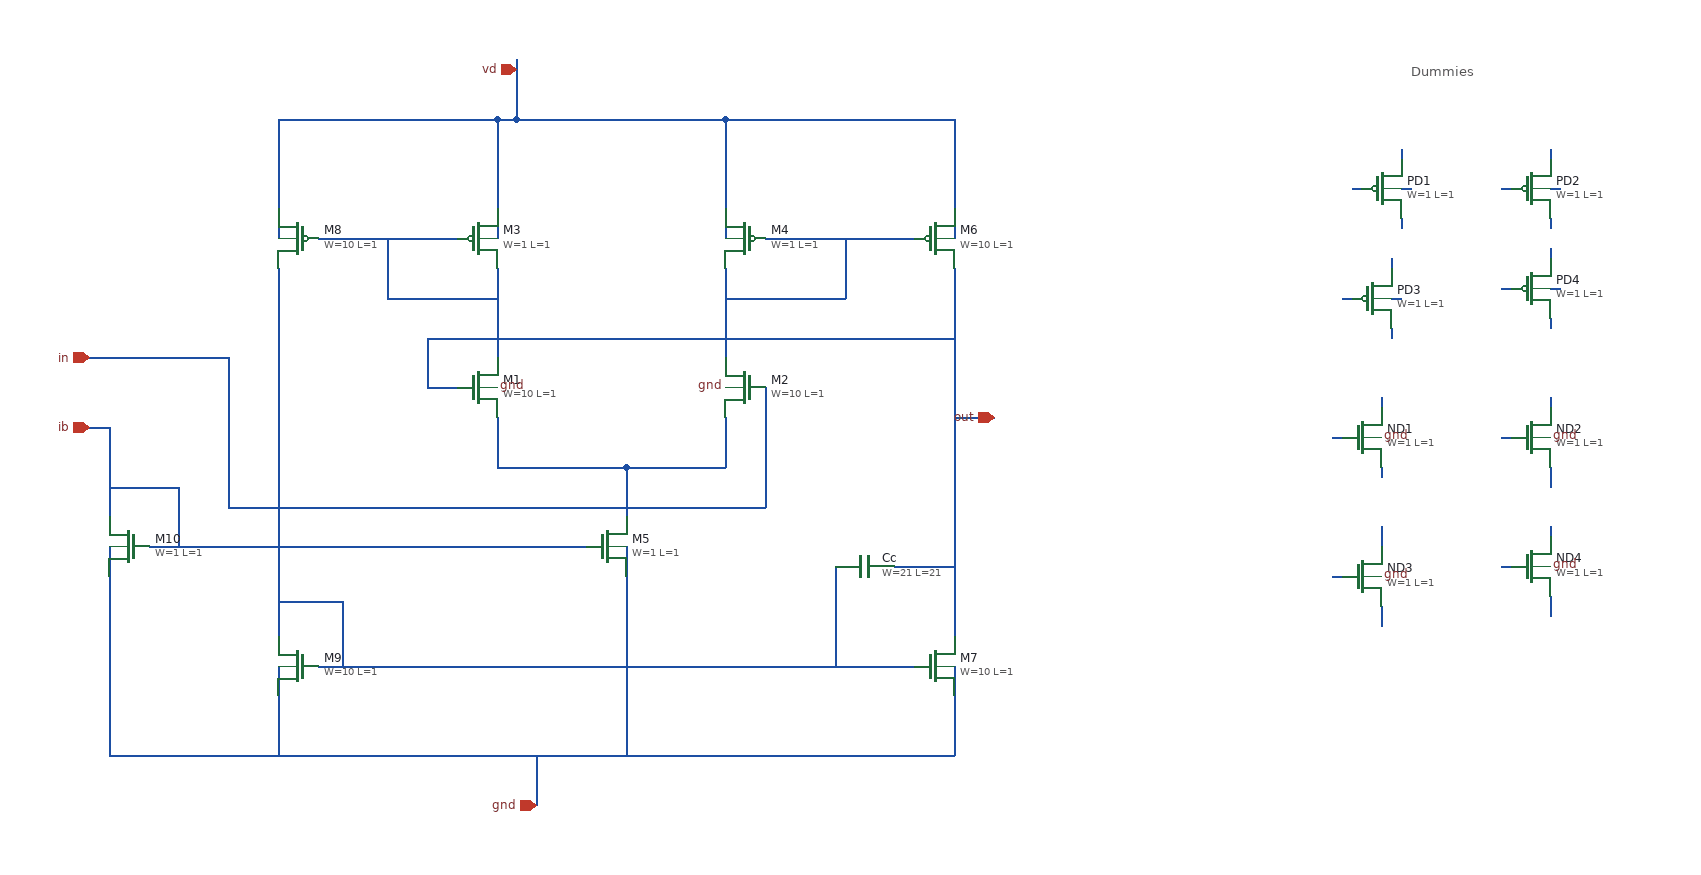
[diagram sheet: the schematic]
v {xschem version=3.4.2 file_version=1.2
* Copyright 2020 Stefan Frederik Schippers
* 
* Licensed under the Apache License, Version 2.0 (the "License");
* you may not use this file except in compliance with the License.
* You may obtain a copy of the License at
*
*     https://www.apache.org/licenses/LICENSE-2.0
*
* Unless required by applicable law or agreed to in writing, software
* distributed under the License is distributed on an "AS IS" BASIS,
* WITHOUT WARRANTIES OR CONDITIONS OF ANY KIND, either express or implied.
* See the License for the specific language governing permissions and
* limitations under the License.

}
G {}
K {}
V {}
S {}
E {}
T {Dummies} 1300 -1980 0 0 0.4 0.4 {}
N -40 -1610 -10 -1610 { lab=ib}
N 400 -1980 400 -1920 { lab=vd}
N 380 -1920 400 -1920 {
lab=vd}
N 380 -1920 380 -1830 {
lab=vd}
N 380 -1830 380 -1800 {
lab=vd}
N 160 -1920 380 -1920 {
lab=vd}
N 160 -1920 160 -1830 {
lab=vd}
N 400 -1920 610 -1920 {
lab=vd}
N 610 -1920 610 -1830 {
lab=vd}
N -10 -1610 -10 -1520 {
lab=ib}
N -10 -1490 -10 -1460 {
lab=gnd}
N 160 -1830 160 -1800 {
lab=vd}
N 610 -1830 610 -1800 {
lab=vd}
N 160 -1770 160 -1400 {
lab=#net1}
N 160 -1370 160 -1340 {
lab=gnd}
N 200 -1370 800 -1370 {
lab=#net1}
N 380 -1770 380 -1680 {
lab=#net2}
N 610 -1770 610 -1680 {
lab=#net3}
N 200 -1800 340 -1800 {
lab=#net2}
N 270 -1740 380 -1740 {
lab=#net2}
N 270 -1800 270 -1740 {
lab=#net2}
N 650 -1800 800 -1800 {
lab=#net3}
N 610 -1740 730 -1740 {
lab=#net3}
N 730 -1800 730 -1740 {
lab=#net3}
N 610 -1920 840 -1920 {
lab=vd}
N 840 -1920 840 -1830 {
lab=vd}
N 840 -1830 840 -1800 {
lab=vd}
N 840 -1770 840 -1400 {
lab=out}
N 840 -1370 840 -1340 {
lab=gnd}
N 840 -1620 880 -1620 {
lab=out}
N 310 -1650 340 -1650 {
lab=out}
N 310 -1700 310 -1650 {
lab=out}
N 310 -1700 840 -1700 {
lab=out}
N 30 -1490 470 -1490 {
lab=ib}
N 380 -1620 380 -1570 {
lab=#net4}
N 380 -1570 510 -1570 {
lab=#net4}
N 510 -1570 510 -1520 {
lab=#net4}
N 510 -1490 510 -1460 {
lab=gnd}
N 510 -1570 610 -1570 {
lab=#net4}
N 610 -1620 610 -1570 {
lab=#net4}
N 650 -1650 650 -1530 {
lab=in}
N 110 -1530 650 -1530 {
lab=in}
N 110 -1680 110 -1530 {
lab=in}
N -40 -1680 110 -1680 {
lab=in}
N -10 -1460 -10 -1280 {
lab=gnd}
N -10 -1280 840 -1280 {
lab=gnd}
N 840 -1340 840 -1280 {
lab=gnd}
N 160 -1340 160 -1280 {
lab=gnd}
N 510 -1460 510 -1280 {
lab=gnd}
N 420 -1280 420 -1230 {
lab=gnd}
N -10 -1550 60 -1550 {
lab=ib}
N 60 -1550 60 -1490 {
lab=ib}
N 160 -1435 225 -1435 {
lab=#net1}
N 225 -1435 225 -1370 {
lab=#net1}
N 1290 -1850 1300 -1850 {
lab=#net5}
N 1290 -1890 1290 -1880 {
lab=#net6}
N 1240 -1850 1250 -1850 {
lab=#net7}
N 1290 -1820 1290 -1810 {
lab=#net8}
N 1440 -1850 1450 -1850 {
lab=#net9}
N 1440 -1890 1440 -1880 {
lab=#net10}
N 1390 -1850 1400 -1850 {
lab=#net11}
N 1440 -1820 1440 -1810 {
lab=#net12}
N 1280 -1740 1290 -1740 {
lab=#net13}
N 1280 -1780 1280 -1770 {
lab=#net14}
N 1230 -1740 1240 -1740 {
lab=#net15}
N 1280 -1710 1280 -1700 {
lab=#net16}
N 1440 -1750 1450 -1750 {
lab=#net17}
N 1440 -1790 1440 -1780 {
lab=#net18}
N 1390 -1750 1400 -1750 {
lab=#net19}
N 1440 -1720 1440 -1710 {
lab=#net20}
N 1220 -1600 1230 -1600 {
lab=#net21}
N 1390 -1600 1400 -1600 {
lab=#net22}
N 1220 -1460 1230 -1460 {
lab=#net23}
N 1390 -1470 1400 -1470 {
lab=#net24}
N 1270 -1640 1270 -1630 {
lab=#net25}
N 1270 -1570 1270 -1560 {
lab=#net26}
N 1440 -1640 1440 -1630 {
lab=#net27}
N 1440 -1570 1440 -1550 {
lab=#net28}
N 1270 -1510 1270 -1490 {
lab=#net29}
N 1270 -1430 1270 -1410 {
lab=#net30}
N 1440 -1440 1440 -1420 {
lab=#net31}
N 1440 -1510 1440 -1500 {
lab=#net32}
N 720 -1470 720 -1370 {
lab=#net1}
N 780 -1470 840 -1470 {
lab=out}
C {devices/iopin.sym} 400 -1970 3 0 {name=p2 lab=vd}
C {devices/iopin.sym} -30 -1610 2 0 {name=p1 lab=ib}
C {sky130_fd_pr/pfet_01v8.sym} 360 -1800 0 0 {name=M3
L=1
W=1
nf=1
mult=1
ad="'int((nf+1)/2) * W/nf * 0.29'" 
pd="'2*int((nf+1)/2) * (W/nf + 0.29)'"
as="'int((nf+2)/2) * W/nf * 0.29'" 
ps="'2*int((nf+2)/2) * (W/nf + 0.29)'"
nrd="'0.29 / W'" nrs="'0.29 / W'"
sa=0 sb=0 sd=0
model=pfet_01v8
spiceprefix=X
}
C {sky130_fd_pr/nfet_01v8.sym} 360 -1650 0 0 {name=M1
L=1
W=10
nf=10 
mult=1
ad="'int((nf+1)/2) * W/nf * 0.29'" 
pd="'2*int((nf+1)/2) * (W/nf + 0.29)'"
as="'int((nf+2)/2) * W/nf * 0.29'" 
ps="'2*int((nf+2)/2) * (W/nf + 0.29)'"
nrd="'0.29 / W'" nrs="'0.29 / W'"
sa=0 sb=0 sd=0
model=nfet_01v8
spiceprefix=X
}
C {sky130_fd_pr/nfet_01v8.sym} 630 -1650 0 1 {name=M2
L=1
W=10
nf=10 
mult=1
ad="'int((nf+1)/2) * W/nf * 0.29'" 
pd="'2*int((nf+1)/2) * (W/nf + 0.29)'"
as="'int((nf+2)/2) * W/nf * 0.29'" 
ps="'2*int((nf+2)/2) * (W/nf + 0.29)'"
nrd="'0.29 / W'" nrs="'0.29 / W'"
sa=0 sb=0 sd=0
model=nfet_01v8
spiceprefix=X
}
C {sky130_fd_pr/pfet_01v8.sym} 630 -1800 0 1 {name=M4
L=1
W=1
nf=1
mult=1
ad="'int((nf+1)/2) * W/nf * 0.29'" 
pd="'2*int((nf+1)/2) * (W/nf + 0.29)'"
as="'int((nf+2)/2) * W/nf * 0.29'" 
ps="'2*int((nf+2)/2) * (W/nf + 0.29)'"
nrd="'0.29 / W'" nrs="'0.29 / W'"
sa=0 sb=0 sd=0
model=pfet_01v8
spiceprefix=X
}
C {sky130_fd_pr/nfet_01v8.sym} 490 -1490 0 0 {name=M5
L=1
W=1
nf=1 
mult=1
ad="'int((nf+1)/2) * W/nf * 0.29'" 
pd="'2*int((nf+1)/2) * (W/nf + 0.29)'"
as="'int((nf+2)/2) * W/nf * 0.29'" 
ps="'2*int((nf+2)/2) * (W/nf + 0.29)'"
nrd="'0.29 / W'" nrs="'0.29 / W'"
sa=0 sb=0 sd=0
model=nfet_01v8
spiceprefix=X
}
C {sky130_fd_pr/pfet_01v8.sym} 820 -1800 0 0 {name=M6
L=1
W=10
nf=10
mult=1
ad="'int((nf+1)/2) * W/nf * 0.29'" 
pd="'2*int((nf+1)/2) * (W/nf + 0.29)'"
as="'int((nf+2)/2) * W/nf * 0.29'" 
ps="'2*int((nf+2)/2) * (W/nf + 0.29)'"
nrd="'0.29 / W'" nrs="'0.29 / W'"
sa=0 sb=0 sd=0
model=pfet_01v8
spiceprefix=X
}
C {sky130_fd_pr/nfet_01v8.sym} 820 -1370 0 0 {name=M7
L=1
W=10
nf=10 
mult=1
ad="'int((nf+1)/2) * W/nf * 0.29'" 
pd="'2*int((nf+1)/2) * (W/nf + 0.29)'"
as="'int((nf+2)/2) * W/nf * 0.29'" 
ps="'2*int((nf+2)/2) * (W/nf + 0.29)'"
nrd="'0.29 / W'" nrs="'0.29 / W'"
sa=0 sb=0 sd=0
model=nfet_01v8
spiceprefix=X
}
C {sky130_fd_pr/pfet_01v8.sym} 180 -1800 0 1 {name=M8
L=1
W=10
nf=10
mult=1
ad="'int((nf+1)/2) * W/nf * 0.29'" 
pd="'2*int((nf+1)/2) * (W/nf + 0.29)'"
as="'int((nf+2)/2) * W/nf * 0.29'" 
ps="'2*int((nf+2)/2) * (W/nf + 0.29)'"
nrd="'0.29 / W'" nrs="'0.29 / W'"
sa=0 sb=0 sd=0
model=pfet_01v8
spiceprefix=X
}
C {sky130_fd_pr/nfet_01v8.sym} 180 -1370 0 1 {name=M9
L=1
W=10
nf=10 
mult=1
ad="'int((nf+1)/2) * W/nf * 0.29'" 
pd="'2*int((nf+1)/2) * (W/nf + 0.29)'"
as="'int((nf+2)/2) * W/nf * 0.29'" 
ps="'2*int((nf+2)/2) * (W/nf + 0.29)'"
nrd="'0.29 / W'" nrs="'0.29 / W'"
sa=0 sb=0 sd=0
model=nfet_01v8
spiceprefix=X
}
C {sky130_fd_pr/nfet_01v8.sym} 10 -1490 0 1 {name=M10
L=1
W=1
nf=1 
mult=1
ad="'int((nf+1)/2) * W/nf * 0.29'" 
pd="'2*int((nf+1)/2) * (W/nf + 0.29)'"
as="'int((nf+2)/2) * W/nf * 0.29'" 
ps="'2*int((nf+2)/2) * (W/nf + 0.29)'"
nrd="'0.29 / W'" nrs="'0.29 / W'"
sa=0 sb=0 sd=0
model=nfet_01v8
spiceprefix=X
}
C {devices/iopin.sym} 880 -1620 0 0 {name=p3 lab=out}
C {devices/iopin.sym} -30 -1680 2 0 {name=p4 lab=in}
C {devices/iopin.sym} 420 -1230 1 0 {name=p5 lab=gnd}
C {devices/lab_pin.sym} 380 -1650 0 1 {name=l1 sig_type=std_logic lab=gnd}
C {devices/lab_pin.sym} 610 -1650 0 0 {name=l2 sig_type=std_logic lab=gnd}
C {sky130_fd_pr/pfet_01v8.sym} 1270 -1850 0 0 {name=PD1
L=1
W=1
nf=1
mult=1
ad="'int((nf+1)/2) * W/nf * 0.29'" 
pd="'2*int((nf+1)/2) * (W/nf + 0.29)'"
as="'int((nf+2)/2) * W/nf * 0.29'" 
ps="'2*int((nf+2)/2) * (W/nf + 0.29)'"
nrd="'0.29 / W'" nrs="'0.29 / W'"
sa=0 sb=0 sd=0
model=pfet_01v8
spiceprefix=X
}
C {sky130_fd_pr/pfet_01v8.sym} 1420 -1850 0 0 {name=PD2
L=1
W=1
nf=1
mult=1
ad="'int((nf+1)/2) * W/nf * 0.29'" 
pd="'2*int((nf+1)/2) * (W/nf + 0.29)'"
as="'int((nf+2)/2) * W/nf * 0.29'" 
ps="'2*int((nf+2)/2) * (W/nf + 0.29)'"
nrd="'0.29 / W'" nrs="'0.29 / W'"
sa=0 sb=0 sd=0
model=pfet_01v8
spiceprefix=X
}
C {sky130_fd_pr/pfet_01v8.sym} 1260 -1740 0 0 {name=PD3
L=1
W=1
nf=1
mult=1
ad="'int((nf+1)/2) * W/nf * 0.29'" 
pd="'2*int((nf+1)/2) * (W/nf + 0.29)'"
as="'int((nf+2)/2) * W/nf * 0.29'" 
ps="'2*int((nf+2)/2) * (W/nf + 0.29)'"
nrd="'0.29 / W'" nrs="'0.29 / W'"
sa=0 sb=0 sd=0
model=pfet_01v8
spiceprefix=X
}
C {sky130_fd_pr/pfet_01v8.sym} 1420 -1750 0 0 {name=PD4
L=1
W=1
nf=1
mult=1
ad="'int((nf+1)/2) * W/nf * 0.29'" 
pd="'2*int((nf+1)/2) * (W/nf + 0.29)'"
as="'int((nf+2)/2) * W/nf * 0.29'" 
ps="'2*int((nf+2)/2) * (W/nf + 0.29)'"
nrd="'0.29 / W'" nrs="'0.29 / W'"
sa=0 sb=0 sd=0
model=pfet_01v8
spiceprefix=X
}
C {sky130_fd_pr/nfet_01v8.sym} 1250 -1600 0 0 {name=ND1
L=1
W=1
nf=1
mult=1
ad="'int((nf+1)/2) * W/nf * 0.29'" 
pd="'2*int((nf+1)/2) * (W/nf + 0.29)'"
as="'int((nf+2)/2) * W/nf * 0.29'" 
ps="'2*int((nf+2)/2) * (W/nf + 0.29)'"
nrd="'0.29 / W'" nrs="'0.29 / W'"
sa=0 sb=0 sd=0
model=nfet_01v8
spiceprefix=X
}
C {devices/lab_pin.sym} 1270 -1600 0 1 {name=l3 sig_type=std_logic lab=gnd}
C {sky130_fd_pr/nfet_01v8.sym} 1420 -1600 0 0 {name=ND2
L=1
W=1
nf=1 
mult=1
ad="'int((nf+1)/2) * W/nf * 0.29'" 
pd="'2*int((nf+1)/2) * (W/nf + 0.29)'"
as="'int((nf+2)/2) * W/nf * 0.29'" 
ps="'2*int((nf+2)/2) * (W/nf + 0.29)'"
nrd="'0.29 / W'" nrs="'0.29 / W'"
sa=0 sb=0 sd=0
model=nfet_01v8
spiceprefix=X
}
C {devices/lab_pin.sym} 1440 -1600 0 1 {name=l4 sig_type=std_logic lab=gnd}
C {sky130_fd_pr/nfet_01v8.sym} 1250 -1460 0 0 {name=ND3
L=1
W=1
nf=1 
mult=1
ad="'int((nf+1)/2) * W/nf * 0.29'" 
pd="'2*int((nf+1)/2) * (W/nf + 0.29)'"
as="'int((nf+2)/2) * W/nf * 0.29'" 
ps="'2*int((nf+2)/2) * (W/nf + 0.29)'"
nrd="'0.29 / W'" nrs="'0.29 / W'"
sa=0 sb=0 sd=0
model=nfet_01v8
spiceprefix=X
}
C {devices/lab_pin.sym} 1270 -1460 0 1 {name=l5 sig_type=std_logic lab=gnd}
C {sky130_fd_pr/nfet_01v8.sym} 1420 -1470 0 0 {name=ND4
L=1
W=1
nf=1 
mult=1
ad="'int((nf+1)/2) * W/nf * 0.29'" 
pd="'2*int((nf+1)/2) * (W/nf + 0.29)'"
as="'int((nf+2)/2) * W/nf * 0.29'" 
ps="'2*int((nf+2)/2) * (W/nf + 0.29)'"
nrd="'0.29 / W'" nrs="'0.29 / W'"
sa=0 sb=0 sd=0
model=nfet_01v8
spiceprefix=X
}
C {devices/lab_pin.sym} 1440 -1470 0 1 {name=l6 sig_type=std_logic lab=gnd}
C {sky130_fd_pr/cap_mim_m3_2.sym} 750 -1470 1 0 {name=Cc model=cap_mim_m3_2 W=21 L=21 MF=1 spiceprefix=X}
